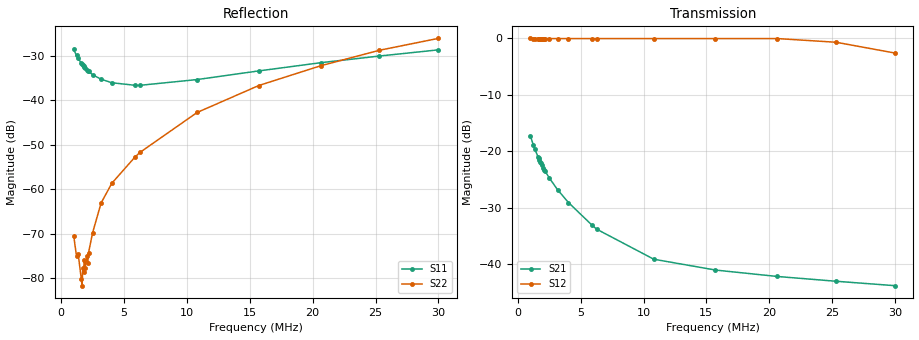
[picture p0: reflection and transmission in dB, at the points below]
! ListType=Log
!!FT85-52 x2 10T CMR
# MHZ S RI R 50
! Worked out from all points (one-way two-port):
!   101 points, 1 MHz to 30 MHz, reference 50 ohm
!   highest |S21| = -17.22 dB at 1 MHz (marker M1); lowest = -43.8 dB at 30 MHz (marker M2)
!   lowest |S11| = -36.6 dB at 6.275 MHz (marker M3), VSWR 1.03, Z = 50.4 + j1.43 ohm
!   |S11| at or under -10 dB: start of sweep to end of sweep
!   |S22| runs from -81.7 to -26.1 dB; largest |S21 - S12| = 1
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1  -0.0137 0.0348  0.0539 -0.1267  1.002 0.0243  -0.000132 0.00027
1.226386  -0.00945 0.0306  0.0381 -0.1087  0.9978 0.0133  -0.000123 0.000128
1.358129  -0.00777 0.0286  0.0318 -0.1  0.9976 0.00971  -0.000154 0.000106
1.609893  -0.00535 0.0256  0.0235 -0.0865  0.9978 0.00559  -9.45e-05 2.12e-05
1.66559  -0.00495 0.025  0.0221 -0.0839  0.9978 0.00497  -8.23e-05 2.6e-06
1.723215  -0.00458 0.0244  0.0207 -0.0814  0.9978 0.00441  -0.00013 -1.75e-05
1.782833  -0.00418 0.024  0.0195 -0.0789  0.9979 0.00389  -0.000117 -2.1e-05
1.844513  -0.00385 0.0234  0.0183 -0.0765  0.998 0.00341  -0.000139 -8e-05
1.908328  -0.00351 0.0229  0.0172 -0.0742  0.998 0.003  -0.000111 -6.66e-05
2.042657  -0.00287 0.022  0.0152 -0.0696  0.9981 0.00227  -0.000136 -0.000111
2.113327  -0.00257 0.0215  0.0143 -0.0674  0.9982 0.00195  -7.31e-05 -0.000131
2.186442  -0.00227 0.0211  0.0134 -0.0653  0.9982 0.0017  -6.29e-05 -0.000184
2.505087  -0.00123 0.0194  0.0104 -0.0573  0.9983 0.00095  -9.06e-05 -0.000312
3.178493  0.000331 0.0173  0.00674 -0.0451  0.9981 0.000778  -0.000106 -0.000692
4.032921  0.00169 0.0157  0.00439 -0.035  0.9979 0.00135  -0.000149 -0.00116
5.862773  0.00375 0.0143  0.00284 -0.0223  0.9979 0.00265  -0.000145 -0.00229
6.275459  0.00409 0.0142  0.00287 -0.0203  0.9979 0.003  -0.000116 -0.0026
10.81396  0.00814 0.0151  0.00486 -0.01  0.9978 0.00812  -6.12e-05 -0.00731
15.72057  0.0136 0.0166  0.00568 -0.00687  0.9979 0.0162  0.000175 -0.0147
20.63659  0.0202 0.0172  0.00575 -0.0053  0.9977 0.0269  0.000667 -0.0245
25.30843  0.027 0.0163  0.00562 -0.00433  0.9255 0.0272  0.0104 -0.0351
30  0.0343 0.0139  0.00543 -0.00354  0.741 -0.0505  0.0326 -0.0377
